VERSION 5.8 ;
BUSBITCHARS "[]" ;
DIVIDERCHAR "/" ;
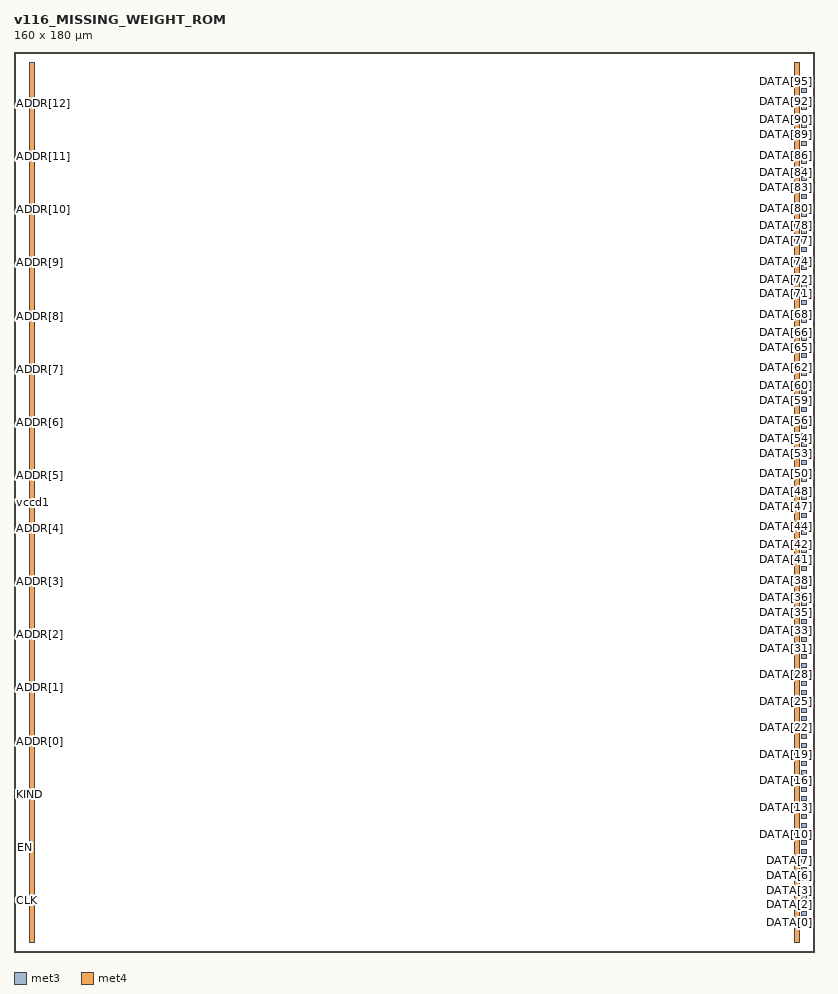
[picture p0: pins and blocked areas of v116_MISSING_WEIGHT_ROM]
MACRO v116_MISSING_WEIGHT_ROM
  CLASS BLOCK ;
  ORIGIN 0 0 ;
  FOREIGN v116_MISSING_WEIGHT_ROM 0 0 ;
  SIZE 160 BY 180 ;
  SYMMETRY X Y ;
  PIN CLK
   DIRECTION INPUT ;
   USE SIGNAL ;
   PORT
    LAYER met3 ;
    RECT 1.6000 9.9125 2.6000 10.7125 ;
   END
  END CLK
  PIN EN
   DIRECTION INPUT ;
   USE SIGNAL ;
   PORT
    LAYER met3 ;
    RECT 1.6000 20.5375 2.6000 21.3375 ;
   END
  END EN
  PIN KIND
   DIRECTION INPUT ;
   USE SIGNAL ;
   PORT
    LAYER met3 ;
    RECT 1.6000 31.1625 2.6000 31.9625 ;
   END
  END KIND
  PIN ADDR[0]
   DIRECTION INPUT ;
   USE SIGNAL ;
   PORT
    LAYER met3 ;
    RECT 1.6000 41.7875 2.6000 42.5875 ;
   END
  END ADDR[0]
  PIN ADDR[1]
   DIRECTION INPUT ;
   USE SIGNAL ;
   PORT
    LAYER met3 ;
    RECT 1.6000 52.4125 2.6000 53.2125 ;
   END
  END ADDR[1]
  PIN ADDR[2]
   DIRECTION INPUT ;
   USE SIGNAL ;
   PORT
    LAYER met3 ;
    RECT 1.6000 63.0375 2.6000 63.8375 ;
   END
  END ADDR[2]
  PIN ADDR[3]
   DIRECTION INPUT ;
   USE SIGNAL ;
   PORT
    LAYER met3 ;
    RECT 1.6000 73.6625 2.6000 74.4625 ;
   END
  END ADDR[3]
  PIN ADDR[4]
   DIRECTION INPUT ;
   USE SIGNAL ;
   PORT
    LAYER met3 ;
    RECT 1.6000 84.2875 2.6000 85.0875 ;
   END
  END ADDR[4]
  PIN ADDR[5]
   DIRECTION INPUT ;
   USE SIGNAL ;
   PORT
    LAYER met3 ;
    RECT 1.6000 94.9125 2.6000 95.7125 ;
   END
  END ADDR[5]
  PIN ADDR[6]
   DIRECTION INPUT ;
   USE SIGNAL ;
   PORT
    LAYER met3 ;
    RECT 1.6000 105.5375 2.6000 106.3375 ;
   END
  END ADDR[6]
  PIN ADDR[7]
   DIRECTION INPUT ;
   USE SIGNAL ;
   PORT
    LAYER met3 ;
    RECT 1.6000 116.1625 2.6000 116.9625 ;
   END
  END ADDR[7]
  PIN ADDR[8]
   DIRECTION INPUT ;
   USE SIGNAL ;
   PORT
    LAYER met3 ;
    RECT 1.6000 126.7875 2.6000 127.5875 ;
   END
  END ADDR[8]
  PIN ADDR[9]
   DIRECTION INPUT ;
   USE SIGNAL ;
   PORT
    LAYER met3 ;
    RECT 1.6000 137.4125 2.6000 138.2125 ;
   END
  END ADDR[9]
  PIN ADDR[10]
   DIRECTION INPUT ;
   USE SIGNAL ;
   PORT
    LAYER met3 ;
    RECT 1.6000 148.0375 2.6000 148.8375 ;
   END
  END ADDR[10]
  PIN ADDR[11]
   DIRECTION INPUT ;
   USE SIGNAL ;
   PORT
    LAYER met3 ;
    RECT 1.6000 158.6625 2.6000 159.4625 ;
   END
  END ADDR[11]
  PIN ADDR[12]
   DIRECTION INPUT ;
   USE SIGNAL ;
   PORT
    LAYER met3 ;
    RECT 1.6000 169.2875 2.6000 170.0875 ;
   END
  END ADDR[12]
  PIN DATA[0]
   DIRECTION OUTPUT ;
   USE SIGNAL ;
   PORT
    LAYER met3 ;
    RECT 157.4000 5.4854 158.4000 6.2854 ;
   END
  END DATA[0]
  PIN DATA[1]
   DIRECTION OUTPUT ;
   USE SIGNAL ;
   PORT
    LAYER met3 ;
    RECT 157.4000 7.2562 158.4000 8.0563 ;
   END
  END DATA[1]
  PIN DATA[2]
   DIRECTION OUTPUT ;
   USE SIGNAL ;
   PORT
    LAYER met3 ;
    RECT 157.4000 9.0271 158.4000 9.8271 ;
   END
  END DATA[2]
  PIN DATA[3]
   DIRECTION OUTPUT ;
   USE SIGNAL ;
   PORT
    LAYER met3 ;
    RECT 157.4000 10.7979 158.4000 11.5979 ;
   END
  END DATA[3]
  PIN DATA[4]
   DIRECTION OUTPUT ;
   USE SIGNAL ;
   PORT
    LAYER met3 ;
    RECT 157.4000 12.5687 158.4000 13.3688 ;
   END
  END DATA[4]
  PIN DATA[5]
   DIRECTION OUTPUT ;
   USE SIGNAL ;
   PORT
    LAYER met3 ;
    RECT 157.4000 14.3396 158.4000 15.1396 ;
   END
  END DATA[5]
  PIN DATA[6]
   DIRECTION OUTPUT ;
   USE SIGNAL ;
   PORT
    LAYER met3 ;
    RECT 157.4000 16.1104 158.4000 16.9104 ;
   END
  END DATA[6]
  PIN DATA[7]
   DIRECTION OUTPUT ;
   USE SIGNAL ;
   PORT
    LAYER met3 ;
    RECT 157.4000 17.8813 158.4000 18.6812 ;
   END
  END DATA[7]
  PIN DATA[8]
   DIRECTION OUTPUT ;
   USE SIGNAL ;
   PORT
    LAYER met3 ;
    RECT 157.4000 19.6521 158.4000 20.4521 ;
   END
  END DATA[8]
  PIN DATA[9]
   DIRECTION OUTPUT ;
   USE SIGNAL ;
   PORT
    LAYER met3 ;
    RECT 157.4000 21.4229 158.4000 22.2229 ;
   END
  END DATA[9]
  PIN DATA[10]
   DIRECTION OUTPUT ;
   USE SIGNAL ;
   PORT
    LAYER met3 ;
    RECT 157.4000 23.1938 158.4000 23.9937 ;
   END
  END DATA[10]
  PIN DATA[11]
   DIRECTION OUTPUT ;
   USE SIGNAL ;
   PORT
    LAYER met3 ;
    RECT 157.4000 24.9646 158.4000 25.7646 ;
   END
  END DATA[11]
  PIN DATA[12]
   DIRECTION OUTPUT ;
   USE SIGNAL ;
   PORT
    LAYER met3 ;
    RECT 157.4000 26.7354 158.4000 27.5354 ;
   END
  END DATA[12]
  PIN DATA[13]
   DIRECTION OUTPUT ;
   USE SIGNAL ;
   PORT
    LAYER met3 ;
    RECT 157.4000 28.5063 158.4000 29.3062 ;
   END
  END DATA[13]
  PIN DATA[14]
   DIRECTION OUTPUT ;
   USE SIGNAL ;
   PORT
    LAYER met3 ;
    RECT 157.4000 30.2771 158.4000 31.0771 ;
   END
  END DATA[14]
  PIN DATA[15]
   DIRECTION OUTPUT ;
   USE SIGNAL ;
   PORT
    LAYER met3 ;
    RECT 157.4000 32.0479 158.4000 32.8479 ;
   END
  END DATA[15]
  PIN DATA[16]
   DIRECTION OUTPUT ;
   USE SIGNAL ;
   PORT
    LAYER met3 ;
    RECT 157.4000 33.8188 158.4000 34.6187 ;
   END
  END DATA[16]
  PIN DATA[17]
   DIRECTION OUTPUT ;
   USE SIGNAL ;
   PORT
    LAYER met3 ;
    RECT 157.4000 35.5896 158.4000 36.3896 ;
   END
  END DATA[17]
  PIN DATA[18]
   DIRECTION OUTPUT ;
   USE SIGNAL ;
   PORT
    LAYER met3 ;
    RECT 157.4000 37.3604 158.4000 38.1604 ;
   END
  END DATA[18]
  PIN DATA[19]
   DIRECTION OUTPUT ;
   USE SIGNAL ;
   PORT
    LAYER met3 ;
    RECT 157.4000 39.1313 158.4000 39.9312 ;
   END
  END DATA[19]
  PIN DATA[20]
   DIRECTION OUTPUT ;
   USE SIGNAL ;
   PORT
    LAYER met3 ;
    RECT 157.4000 40.9021 158.4000 41.7021 ;
   END
  END DATA[20]
  PIN DATA[21]
   DIRECTION OUTPUT ;
   USE SIGNAL ;
   PORT
    LAYER met3 ;
    RECT 157.4000 42.6729 158.4000 43.4729 ;
   END
  END DATA[21]
  PIN DATA[22]
   DIRECTION OUTPUT ;
   USE SIGNAL ;
   PORT
    LAYER met3 ;
    RECT 157.4000 44.4438 158.4000 45.2437 ;
   END
  END DATA[22]
  PIN DATA[23]
   DIRECTION OUTPUT ;
   USE SIGNAL ;
   PORT
    LAYER met3 ;
    RECT 157.4000 46.2146 158.4000 47.0146 ;
   END
  END DATA[23]
  PIN DATA[24]
   DIRECTION OUTPUT ;
   USE SIGNAL ;
   PORT
    LAYER met3 ;
    RECT 157.4000 47.9854 158.4000 48.7854 ;
   END
  END DATA[24]
  PIN DATA[25]
   DIRECTION OUTPUT ;
   USE SIGNAL ;
   PORT
    LAYER met3 ;
    RECT 157.4000 49.7563 158.4000 50.5562 ;
   END
  END DATA[25]
  PIN DATA[26]
   DIRECTION OUTPUT ;
   USE SIGNAL ;
   PORT
    LAYER met3 ;
    RECT 157.4000 51.5271 158.4000 52.3271 ;
   END
  END DATA[26]
  PIN DATA[27]
   DIRECTION OUTPUT ;
   USE SIGNAL ;
   PORT
    LAYER met3 ;
    RECT 157.4000 53.2979 158.4000 54.0979 ;
   END
  END DATA[27]
  PIN DATA[28]
   DIRECTION OUTPUT ;
   USE SIGNAL ;
   PORT
    LAYER met3 ;
    RECT 157.4000 55.0688 158.4000 55.8687 ;
   END
  END DATA[28]
  PIN DATA[29]
   DIRECTION OUTPUT ;
   USE SIGNAL ;
   PORT
    LAYER met3 ;
    RECT 157.4000 56.8396 158.4000 57.6396 ;
   END
  END DATA[29]
  PIN DATA[30]
   DIRECTION OUTPUT ;
   USE SIGNAL ;
   PORT
    LAYER met3 ;
    RECT 157.4000 58.6104 158.4000 59.4104 ;
   END
  END DATA[30]
  PIN DATA[31]
   DIRECTION OUTPUT ;
   USE SIGNAL ;
   PORT
    LAYER met3 ;
    RECT 157.4000 60.3813 158.4000 61.1812 ;
   END
  END DATA[31]
  PIN DATA[32]
   DIRECTION OUTPUT ;
   USE SIGNAL ;
   PORT
    LAYER met3 ;
    RECT 157.4000 62.1521 158.4000 62.9521 ;
   END
  END DATA[32]
  PIN DATA[33]
   DIRECTION OUTPUT ;
   USE SIGNAL ;
   PORT
    LAYER met3 ;
    RECT 157.4000 63.9229 158.4000 64.7229 ;
   END
  END DATA[33]
  PIN DATA[34]
   DIRECTION OUTPUT ;
   USE SIGNAL ;
   PORT
    LAYER met3 ;
    RECT 157.4000 65.6937 158.4000 66.4938 ;
   END
  END DATA[34]
  PIN DATA[35]
   DIRECTION OUTPUT ;
   USE SIGNAL ;
   PORT
    LAYER met3 ;
    RECT 157.4000 67.4646 158.4000 68.2646 ;
   END
  END DATA[35]
  PIN DATA[36]
   DIRECTION OUTPUT ;
   USE SIGNAL ;
   PORT
    LAYER met3 ;
    RECT 157.4000 69.2354 158.4000 70.0354 ;
   END
  END DATA[36]
  PIN DATA[37]
   DIRECTION OUTPUT ;
   USE SIGNAL ;
   PORT
    LAYER met3 ;
    RECT 157.4000 71.0062 158.4000 71.8063 ;
   END
  END DATA[37]
  PIN DATA[38]
   DIRECTION OUTPUT ;
   USE SIGNAL ;
   PORT
    LAYER met3 ;
    RECT 157.4000 72.7771 158.4000 73.5771 ;
   END
  END DATA[38]
  PIN DATA[39]
   DIRECTION OUTPUT ;
   USE SIGNAL ;
   PORT
    LAYER met3 ;
    RECT 157.4000 74.5479 158.4000 75.3479 ;
   END
  END DATA[39]
  PIN DATA[40]
   DIRECTION OUTPUT ;
   USE SIGNAL ;
   PORT
    LAYER met3 ;
    RECT 157.4000 76.3187 158.4000 77.1188 ;
   END
  END DATA[40]
  PIN DATA[41]
   DIRECTION OUTPUT ;
   USE SIGNAL ;
   PORT
    LAYER met3 ;
    RECT 157.4000 78.0896 158.4000 78.8896 ;
   END
  END DATA[41]
  PIN DATA[42]
   DIRECTION OUTPUT ;
   USE SIGNAL ;
   PORT
    LAYER met3 ;
    RECT 157.4000 79.8604 158.4000 80.6604 ;
   END
  END DATA[42]
  PIN DATA[43]
   DIRECTION OUTPUT ;
   USE SIGNAL ;
   PORT
    LAYER met3 ;
    RECT 157.4000 81.6312 158.4000 82.4313 ;
   END
  END DATA[43]
  PIN DATA[44]
   DIRECTION OUTPUT ;
   USE SIGNAL ;
   PORT
    LAYER met3 ;
    RECT 157.4000 83.4021 158.4000 84.2021 ;
   END
  END DATA[44]
  PIN DATA[45]
   DIRECTION OUTPUT ;
   USE SIGNAL ;
   PORT
    LAYER met3 ;
    RECT 157.4000 85.1729 158.4000 85.9729 ;
   END
  END DATA[45]
  PIN DATA[46]
   DIRECTION OUTPUT ;
   USE SIGNAL ;
   PORT
    LAYER met3 ;
    RECT 157.4000 86.9437 158.4000 87.7438 ;
   END
  END DATA[46]
  PIN DATA[47]
   DIRECTION OUTPUT ;
   USE SIGNAL ;
   PORT
    LAYER met3 ;
    RECT 157.4000 88.7146 158.4000 89.5146 ;
   END
  END DATA[47]
  PIN DATA[48]
   DIRECTION OUTPUT ;
   USE SIGNAL ;
   PORT
    LAYER met3 ;
    RECT 157.4000 90.4854 158.4000 91.2854 ;
   END
  END DATA[48]
  PIN DATA[49]
   DIRECTION OUTPUT ;
   USE SIGNAL ;
   PORT
    LAYER met3 ;
    RECT 157.4000 92.2562 158.4000 93.0563 ;
   END
  END DATA[49]
  PIN DATA[50]
   DIRECTION OUTPUT ;
   USE SIGNAL ;
   PORT
    LAYER met3 ;
    RECT 157.4000 94.0271 158.4000 94.8271 ;
   END
  END DATA[50]
  PIN DATA[51]
   DIRECTION OUTPUT ;
   USE SIGNAL ;
   PORT
    LAYER met3 ;
    RECT 157.4000 95.7979 158.4000 96.5979 ;
   END
  END DATA[51]
  PIN DATA[52]
   DIRECTION OUTPUT ;
   USE SIGNAL ;
   PORT
    LAYER met3 ;
    RECT 157.4000 97.5687 158.4000 98.3688 ;
   END
  END DATA[52]
  PIN DATA[53]
   DIRECTION OUTPUT ;
   USE SIGNAL ;
   PORT
    LAYER met3 ;
    RECT 157.4000 99.3396 158.4000 100.1396 ;
   END
  END DATA[53]
  PIN DATA[54]
   DIRECTION OUTPUT ;
   USE SIGNAL ;
   PORT
    LAYER met3 ;
    RECT 157.4000 101.1104 158.4000 101.9104 ;
   END
  END DATA[54]
  PIN DATA[55]
   DIRECTION OUTPUT ;
   USE SIGNAL ;
   PORT
    LAYER met3 ;
    RECT 157.4000 102.8812 158.4000 103.6813 ;
   END
  END DATA[55]
  PIN DATA[56]
   DIRECTION OUTPUT ;
   USE SIGNAL ;
   PORT
    LAYER met3 ;
    RECT 157.4000 104.6521 158.4000 105.4521 ;
   END
  END DATA[56]
  PIN DATA[57]
   DIRECTION OUTPUT ;
   USE SIGNAL ;
   PORT
    LAYER met3 ;
    RECT 157.4000 106.4229 158.4000 107.2229 ;
   END
  END DATA[57]
  PIN DATA[58]
   DIRECTION OUTPUT ;
   USE SIGNAL ;
   PORT
    LAYER met3 ;
    RECT 157.4000 108.1937 158.4000 108.9938 ;
   END
  END DATA[58]
  PIN DATA[59]
   DIRECTION OUTPUT ;
   USE SIGNAL ;
   PORT
    LAYER met3 ;
    RECT 157.4000 109.9646 158.4000 110.7646 ;
   END
  END DATA[59]
  PIN DATA[60]
   DIRECTION OUTPUT ;
   USE SIGNAL ;
   PORT
    LAYER met3 ;
    RECT 157.4000 111.7354 158.4000 112.5354 ;
   END
  END DATA[60]
  PIN DATA[61]
   DIRECTION OUTPUT ;
   USE SIGNAL ;
   PORT
    LAYER met3 ;
    RECT 157.4000 113.5062 158.4000 114.3063 ;
   END
  END DATA[61]
  PIN DATA[62]
   DIRECTION OUTPUT ;
   USE SIGNAL ;
   PORT
    LAYER met3 ;
    RECT 157.4000 115.2771 158.4000 116.0771 ;
   END
  END DATA[62]
  PIN DATA[63]
   DIRECTION OUTPUT ;
   USE SIGNAL ;
   PORT
    LAYER met3 ;
    RECT 157.4000 117.0479 158.4000 117.8479 ;
   END
  END DATA[63]
  PIN DATA[64]
   DIRECTION OUTPUT ;
   USE SIGNAL ;
   PORT
    LAYER met3 ;
    RECT 157.4000 118.8187 158.4000 119.6188 ;
   END
  END DATA[64]
  PIN DATA[65]
   DIRECTION OUTPUT ;
   USE SIGNAL ;
   PORT
    LAYER met3 ;
    RECT 157.4000 120.5896 158.4000 121.3896 ;
   END
  END DATA[65]
  PIN DATA[66]
   DIRECTION OUTPUT ;
   USE SIGNAL ;
   PORT
    LAYER met3 ;
    RECT 157.4000 122.3604 158.4000 123.1604 ;
   END
  END DATA[66]
  PIN DATA[67]
   DIRECTION OUTPUT ;
   USE SIGNAL ;
   PORT
    LAYER met3 ;
    RECT 157.4000 124.1312 158.4000 124.9313 ;
   END
  END DATA[67]
  PIN DATA[68]
   DIRECTION OUTPUT ;
   USE SIGNAL ;
   PORT
    LAYER met3 ;
    RECT 157.4000 125.9021 158.4000 126.7021 ;
   END
  END DATA[68]
  PIN DATA[69]
   DIRECTION OUTPUT ;
   USE SIGNAL ;
   PORT
    LAYER met3 ;
    RECT 157.4000 127.6729 158.4000 128.4729 ;
   END
  END DATA[69]
  PIN DATA[70]
   DIRECTION OUTPUT ;
   USE SIGNAL ;
   PORT
    LAYER met3 ;
    RECT 157.4000 129.4437 158.4000 130.2438 ;
   END
  END DATA[70]
  PIN DATA[71]
   DIRECTION OUTPUT ;
   USE SIGNAL ;
   PORT
    LAYER met3 ;
    RECT 157.4000 131.2146 158.4000 132.0146 ;
   END
  END DATA[71]
  PIN DATA[72]
   DIRECTION OUTPUT ;
   USE SIGNAL ;
   PORT
    LAYER met3 ;
    RECT 157.4000 132.9854 158.4000 133.7854 ;
   END
  END DATA[72]
  PIN DATA[73]
   DIRECTION OUTPUT ;
   USE SIGNAL ;
   PORT
    LAYER met3 ;
    RECT 157.4000 134.7562 158.4000 135.5563 ;
   END
  END DATA[73]
  PIN DATA[74]
   DIRECTION OUTPUT ;
   USE SIGNAL ;
   PORT
    LAYER met3 ;
    RECT 157.4000 136.5271 158.4000 137.3271 ;
   END
  END DATA[74]
  PIN DATA[75]
   DIRECTION OUTPUT ;
   USE SIGNAL ;
   PORT
    LAYER met3 ;
    RECT 157.4000 138.2979 158.4000 139.0979 ;
   END
  END DATA[75]
  PIN DATA[76]
   DIRECTION OUTPUT ;
   USE SIGNAL ;
   PORT
    LAYER met3 ;
    RECT 157.4000 140.0687 158.4000 140.8688 ;
   END
  END DATA[76]
  PIN DATA[77]
   DIRECTION OUTPUT ;
   USE SIGNAL ;
   PORT
    LAYER met3 ;
    RECT 157.4000 141.8396 158.4000 142.6396 ;
   END
  END DATA[77]
  PIN DATA[78]
   DIRECTION OUTPUT ;
   USE SIGNAL ;
   PORT
    LAYER met3 ;
    RECT 157.4000 143.6104 158.4000 144.4104 ;
   END
  END DATA[78]
  PIN DATA[79]
   DIRECTION OUTPUT ;
   USE SIGNAL ;
   PORT
    LAYER met3 ;
    RECT 157.4000 145.3812 158.4000 146.1813 ;
   END
  END DATA[79]
  PIN DATA[80]
   DIRECTION OUTPUT ;
   USE SIGNAL ;
   PORT
    LAYER met3 ;
    RECT 157.4000 147.1521 158.4000 147.9521 ;
   END
  END DATA[80]
  PIN DATA[81]
   DIRECTION OUTPUT ;
   USE SIGNAL ;
   PORT
    LAYER met3 ;
    RECT 157.4000 148.9229 158.4000 149.7229 ;
   END
  END DATA[81]
  PIN DATA[82]
   DIRECTION OUTPUT ;
   USE SIGNAL ;
   PORT
    LAYER met3 ;
    RECT 157.4000 150.6937 158.4000 151.4938 ;
   END
  END DATA[82]
  PIN DATA[83]
   DIRECTION OUTPUT ;
   USE SIGNAL ;
   PORT
    LAYER met3 ;
    RECT 157.4000 152.4646 158.4000 153.2646 ;
   END
  END DATA[83]
  PIN DATA[84]
   DIRECTION OUTPUT ;
   USE SIGNAL ;
   PORT
    LAYER met3 ;
    RECT 157.4000 154.2354 158.4000 155.0354 ;
   END
  END DATA[84]
  PIN DATA[85]
   DIRECTION OUTPUT ;
   USE SIGNAL ;
   PORT
    LAYER met3 ;
    RECT 157.4000 156.0062 158.4000 156.8063 ;
   END
  END DATA[85]
  PIN DATA[86]
   DIRECTION OUTPUT ;
   USE SIGNAL ;
   PORT
    LAYER met3 ;
    RECT 157.4000 157.7771 158.4000 158.5771 ;
   END
  END DATA[86]
  PIN DATA[87]
   DIRECTION OUTPUT ;
   USE SIGNAL ;
   PORT
    LAYER met3 ;
    RECT 157.4000 159.5479 158.4000 160.3479 ;
   END
  END DATA[87]
  PIN DATA[88]
   DIRECTION OUTPUT ;
   USE SIGNAL ;
   PORT
    LAYER met3 ;
    RECT 157.4000 161.3187 158.4000 162.1188 ;
   END
  END DATA[88]
  PIN DATA[89]
   DIRECTION OUTPUT ;
   USE SIGNAL ;
   PORT
    LAYER met3 ;
    RECT 157.4000 163.0896 158.4000 163.8896 ;
   END
  END DATA[89]
  PIN DATA[90]
   DIRECTION OUTPUT ;
   USE SIGNAL ;
   PORT
    LAYER met3 ;
    RECT 157.4000 164.8604 158.4000 165.6604 ;
   END
  END DATA[90]
  PIN DATA[91]
   DIRECTION OUTPUT ;
   USE SIGNAL ;
   PORT
    LAYER met3 ;
    RECT 157.4000 166.6312 158.4000 167.4313 ;
   END
  END DATA[91]
  PIN DATA[92]
   DIRECTION OUTPUT ;
   USE SIGNAL ;
   PORT
    LAYER met3 ;
    RECT 157.4000 168.4021 158.4000 169.2021 ;
   END
  END DATA[92]
  PIN DATA[93]
   DIRECTION OUTPUT ;
   USE SIGNAL ;
   PORT
    LAYER met3 ;
    RECT 157.4000 170.1729 158.4000 170.9729 ;
   END
  END DATA[93]
  PIN DATA[94]
   DIRECTION OUTPUT ;
   USE SIGNAL ;
   PORT
    LAYER met3 ;
    RECT 157.4000 171.9437 158.4000 172.7438 ;
   END
  END DATA[94]
  PIN DATA[95]
   DIRECTION OUTPUT ;
   USE SIGNAL ;
   PORT
    LAYER met3 ;
    RECT 157.4000 173.7146 158.4000 174.5146 ;
   END
  END DATA[95]
  PIN vccd1
   DIRECTION INOUT ;
   USE POWER ;
   PORT
    LAYER met4 ;
    RECT 3 2 4 178 ;
   END
  END vccd1
  PIN vssd1
   DIRECTION INOUT ;
   USE GROUND ;
   PORT
    LAYER met4 ;
    RECT 156 2 157 178 ;
   END
  END vssd1
END v116_MISSING_WEIGHT_ROM
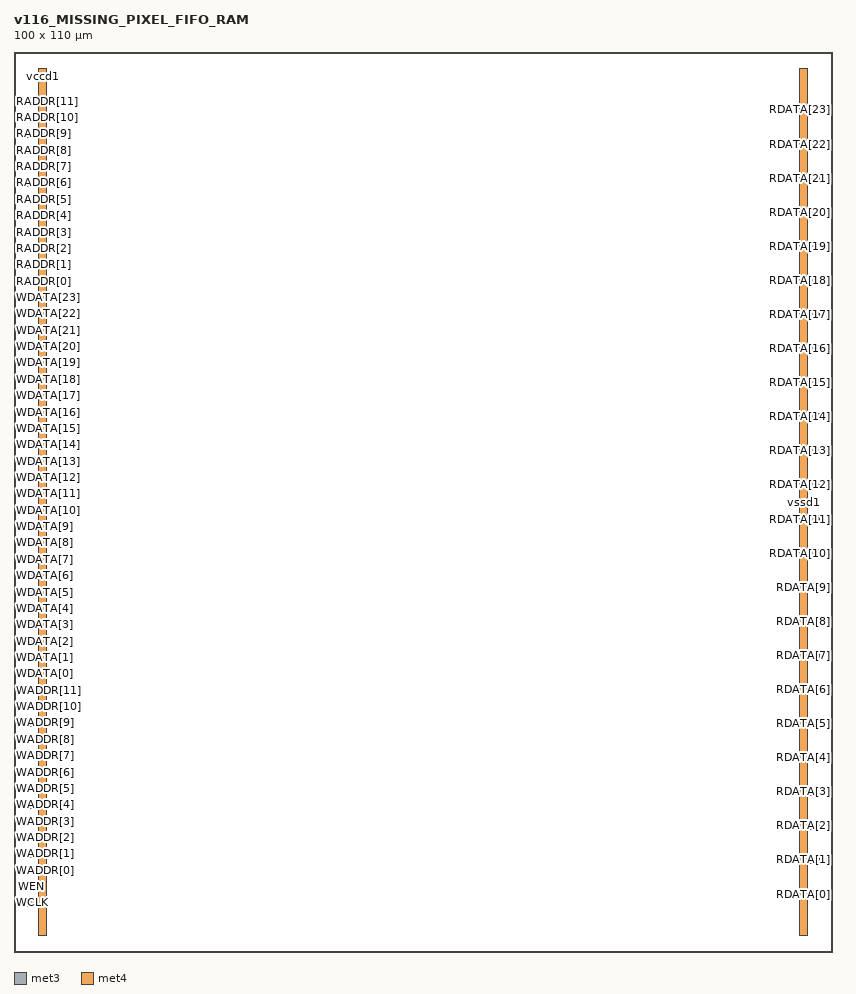
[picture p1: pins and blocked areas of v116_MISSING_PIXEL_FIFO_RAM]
MACRO v116_MISSING_PIXEL_FIFO_RAM
  CLASS BLOCK ;
  ORIGIN 0 0 ;
  FOREIGN v116_MISSING_PIXEL_FIFO_RAM 0 0 ;
  SIZE 100 BY 110 ;
  SYMMETRY X Y ;
  PIN WCLK
   DIRECTION INPUT ;
   USE SIGNAL ;
   PORT
    LAYER met3 ;
    RECT 1.6000 5.6000 2.6000 6.4000 ;
   END
  END WCLK
  PIN WEN
   DIRECTION INPUT ;
   USE SIGNAL ;
   PORT
    LAYER met3 ;
    RECT 1.6000 7.6000 2.6000 8.4000 ;
   END
  END WEN
  PIN WADDR[0]
   DIRECTION INPUT ;
   USE SIGNAL ;
   PORT
    LAYER met3 ;
    RECT 1.6000 9.6000 2.6000 10.4000 ;
   END
  END WADDR[0]
  PIN WADDR[1]
   DIRECTION INPUT ;
   USE SIGNAL ;
   PORT
    LAYER met3 ;
    RECT 1.6000 11.6000 2.6000 12.4000 ;
   END
  END WADDR[1]
  PIN WADDR[2]
   DIRECTION INPUT ;
   USE SIGNAL ;
   PORT
    LAYER met3 ;
    RECT 1.6000 13.6000 2.6000 14.4000 ;
   END
  END WADDR[2]
  PIN WADDR[3]
   DIRECTION INPUT ;
   USE SIGNAL ;
   PORT
    LAYER met3 ;
    RECT 1.6000 15.6000 2.6000 16.4000 ;
   END
  END WADDR[3]
  PIN WADDR[4]
   DIRECTION INPUT ;
   USE SIGNAL ;
   PORT
    LAYER met3 ;
    RECT 1.6000 17.6000 2.6000 18.4000 ;
   END
  END WADDR[4]
  PIN WADDR[5]
   DIRECTION INPUT ;
   USE SIGNAL ;
   PORT
    LAYER met3 ;
    RECT 1.6000 19.6000 2.6000 20.4000 ;
   END
  END WADDR[5]
  PIN WADDR[6]
   DIRECTION INPUT ;
   USE SIGNAL ;
   PORT
    LAYER met3 ;
    RECT 1.6000 21.6000 2.6000 22.4000 ;
   END
  END WADDR[6]
  PIN WADDR[7]
   DIRECTION INPUT ;
   USE SIGNAL ;
   PORT
    LAYER met3 ;
    RECT 1.6000 23.6000 2.6000 24.4000 ;
   END
  END WADDR[7]
  PIN WADDR[8]
   DIRECTION INPUT ;
   USE SIGNAL ;
   PORT
    LAYER met3 ;
    RECT 1.6000 25.6000 2.6000 26.4000 ;
   END
  END WADDR[8]
  PIN WADDR[9]
   DIRECTION INPUT ;
   USE SIGNAL ;
   PORT
    LAYER met3 ;
    RECT 1.6000 27.6000 2.6000 28.4000 ;
   END
  END WADDR[9]
  PIN WADDR[10]
   DIRECTION INPUT ;
   USE SIGNAL ;
   PORT
    LAYER met3 ;
    RECT 1.6000 29.6000 2.6000 30.4000 ;
   END
  END WADDR[10]
  PIN WADDR[11]
   DIRECTION INPUT ;
   USE SIGNAL ;
   PORT
    LAYER met3 ;
    RECT 1.6000 31.6000 2.6000 32.4000 ;
   END
  END WADDR[11]
  PIN WDATA[0]
   DIRECTION INPUT ;
   USE SIGNAL ;
   PORT
    LAYER met3 ;
    RECT 1.6000 33.6000 2.6000 34.4000 ;
   END
  END WDATA[0]
  PIN WDATA[1]
   DIRECTION INPUT ;
   USE SIGNAL ;
   PORT
    LAYER met3 ;
    RECT 1.6000 35.6000 2.6000 36.4000 ;
   END
  END WDATA[1]
  PIN WDATA[2]
   DIRECTION INPUT ;
   USE SIGNAL ;
   PORT
    LAYER met3 ;
    RECT 1.6000 37.6000 2.6000 38.4000 ;
   END
  END WDATA[2]
  PIN WDATA[3]
   DIRECTION INPUT ;
   USE SIGNAL ;
   PORT
    LAYER met3 ;
    RECT 1.6000 39.6000 2.6000 40.4000 ;
   END
  END WDATA[3]
  PIN WDATA[4]
   DIRECTION INPUT ;
   USE SIGNAL ;
   PORT
    LAYER met3 ;
    RECT 1.6000 41.6000 2.6000 42.4000 ;
   END
  END WDATA[4]
  PIN WDATA[5]
   DIRECTION INPUT ;
   USE SIGNAL ;
   PORT
    LAYER met3 ;
    RECT 1.6000 43.6000 2.6000 44.4000 ;
   END
  END WDATA[5]
  PIN WDATA[6]
   DIRECTION INPUT ;
   USE SIGNAL ;
   PORT
    LAYER met3 ;
    RECT 1.6000 45.6000 2.6000 46.4000 ;
   END
  END WDATA[6]
  PIN WDATA[7]
   DIRECTION INPUT ;
   USE SIGNAL ;
   PORT
    LAYER met3 ;
    RECT 1.6000 47.6000 2.6000 48.4000 ;
   END
  END WDATA[7]
  PIN WDATA[8]
   DIRECTION INPUT ;
   USE SIGNAL ;
   PORT
    LAYER met3 ;
    RECT 1.6000 49.6000 2.6000 50.4000 ;
   END
  END WDATA[8]
  PIN WDATA[9]
   DIRECTION INPUT ;
   USE SIGNAL ;
   PORT
    LAYER met3 ;
    RECT 1.6000 51.6000 2.6000 52.4000 ;
   END
  END WDATA[9]
  PIN WDATA[10]
   DIRECTION INPUT ;
   USE SIGNAL ;
   PORT
    LAYER met3 ;
    RECT 1.6000 53.6000 2.6000 54.4000 ;
   END
  END WDATA[10]
  PIN WDATA[11]
   DIRECTION INPUT ;
   USE SIGNAL ;
   PORT
    LAYER met3 ;
    RECT 1.6000 55.6000 2.6000 56.4000 ;
   END
  END WDATA[11]
  PIN WDATA[12]
   DIRECTION INPUT ;
   USE SIGNAL ;
   PORT
    LAYER met3 ;
    RECT 1.6000 57.6000 2.6000 58.4000 ;
   END
  END WDATA[12]
  PIN WDATA[13]
   DIRECTION INPUT ;
   USE SIGNAL ;
   PORT
    LAYER met3 ;
    RECT 1.6000 59.6000 2.6000 60.4000 ;
   END
  END WDATA[13]
  PIN WDATA[14]
   DIRECTION INPUT ;
   USE SIGNAL ;
   PORT
    LAYER met3 ;
    RECT 1.6000 61.6000 2.6000 62.4000 ;
   END
  END WDATA[14]
  PIN WDATA[15]
   DIRECTION INPUT ;
   USE SIGNAL ;
   PORT
    LAYER met3 ;
    RECT 1.6000 63.6000 2.6000 64.4000 ;
   END
  END WDATA[15]
  PIN WDATA[16]
   DIRECTION INPUT ;
   USE SIGNAL ;
   PORT
    LAYER met3 ;
    RECT 1.6000 65.6000 2.6000 66.4000 ;
   END
  END WDATA[16]
  PIN WDATA[17]
   DIRECTION INPUT ;
   USE SIGNAL ;
   PORT
    LAYER met3 ;
    RECT 1.6000 67.6000 2.6000 68.4000 ;
   END
  END WDATA[17]
  PIN WDATA[18]
   DIRECTION INPUT ;
   USE SIGNAL ;
   PORT
    LAYER met3 ;
    RECT 1.6000 69.6000 2.6000 70.4000 ;
   END
  END WDATA[18]
  PIN WDATA[19]
   DIRECTION INPUT ;
   USE SIGNAL ;
   PORT
    LAYER met3 ;
    RECT 1.6000 71.6000 2.6000 72.4000 ;
   END
  END WDATA[19]
  PIN WDATA[20]
   DIRECTION INPUT ;
   USE SIGNAL ;
   PORT
    LAYER met3 ;
    RECT 1.6000 73.6000 2.6000 74.4000 ;
   END
  END WDATA[20]
  PIN WDATA[21]
   DIRECTION INPUT ;
   USE SIGNAL ;
   PORT
    LAYER met3 ;
    RECT 1.6000 75.6000 2.6000 76.4000 ;
   END
  END WDATA[21]
  PIN WDATA[22]
   DIRECTION INPUT ;
   USE SIGNAL ;
   PORT
    LAYER met3 ;
    RECT 1.6000 77.6000 2.6000 78.4000 ;
   END
  END WDATA[22]
  PIN WDATA[23]
   DIRECTION INPUT ;
   USE SIGNAL ;
   PORT
    LAYER met3 ;
    RECT 1.6000 79.6000 2.6000 80.4000 ;
   END
  END WDATA[23]
  PIN RADDR[0]
   DIRECTION INPUT ;
   USE SIGNAL ;
   PORT
    LAYER met3 ;
    RECT 1.6000 81.6000 2.6000 82.4000 ;
   END
  END RADDR[0]
  PIN RADDR[1]
   DIRECTION INPUT ;
   USE SIGNAL ;
   PORT
    LAYER met3 ;
    RECT 1.6000 83.6000 2.6000 84.4000 ;
   END
  END RADDR[1]
  PIN RADDR[2]
   DIRECTION INPUT ;
   USE SIGNAL ;
   PORT
    LAYER met3 ;
    RECT 1.6000 85.6000 2.6000 86.4000 ;
   END
  END RADDR[2]
  PIN RADDR[3]
   DIRECTION INPUT ;
   USE SIGNAL ;
   PORT
    LAYER met3 ;
    RECT 1.6000 87.6000 2.6000 88.4000 ;
   END
  END RADDR[3]
  PIN RADDR[4]
   DIRECTION INPUT ;
   USE SIGNAL ;
   PORT
    LAYER met3 ;
    RECT 1.6000 89.6000 2.6000 90.4000 ;
   END
  END RADDR[4]
  PIN RADDR[5]
   DIRECTION INPUT ;
   USE SIGNAL ;
   PORT
    LAYER met3 ;
    RECT 1.6000 91.6000 2.6000 92.4000 ;
   END
  END RADDR[5]
  PIN RADDR[6]
   DIRECTION INPUT ;
   USE SIGNAL ;
   PORT
    LAYER met3 ;
    RECT 1.6000 93.6000 2.6000 94.4000 ;
   END
  END RADDR[6]
  PIN RADDR[7]
   DIRECTION INPUT ;
   USE SIGNAL ;
   PORT
    LAYER met3 ;
    RECT 1.6000 95.6000 2.6000 96.4000 ;
   END
  END RADDR[7]
  PIN RADDR[8]
   DIRECTION INPUT ;
   USE SIGNAL ;
   PORT
    LAYER met3 ;
    RECT 1.6000 97.6000 2.6000 98.4000 ;
   END
  END RADDR[8]
  PIN RADDR[9]
   DIRECTION INPUT ;
   USE SIGNAL ;
   PORT
    LAYER met3 ;
    RECT 1.6000 99.6000 2.6000 100.4000 ;
   END
  END RADDR[9]
  PIN RADDR[10]
   DIRECTION INPUT ;
   USE SIGNAL ;
   PORT
    LAYER met3 ;
    RECT 1.6000 101.6000 2.6000 102.4000 ;
   END
  END RADDR[10]
  PIN RADDR[11]
   DIRECTION INPUT ;
   USE SIGNAL ;
   PORT
    LAYER met3 ;
    RECT 1.6000 103.6000 2.6000 104.4000 ;
   END
  END RADDR[11]
  PIN RDATA[0]
   DIRECTION OUTPUT ;
   USE SIGNAL ;
   PORT
    LAYER met3 ;
    RECT 97.4000 6.6833 98.4000 7.4833 ;
   END
  END RDATA[0]
  PIN RDATA[1]
   DIRECTION OUTPUT ;
   USE SIGNAL ;
   PORT
    LAYER met3 ;
    RECT 97.4000 10.8500 98.4000 11.6500 ;
   END
  END RDATA[1]
  PIN RDATA[2]
   DIRECTION OUTPUT ;
   USE SIGNAL ;
   PORT
    LAYER met3 ;
    RECT 97.4000 15.0167 98.4000 15.8167 ;
   END
  END RDATA[2]
  PIN RDATA[3]
   DIRECTION OUTPUT ;
   USE SIGNAL ;
   PORT
    LAYER met3 ;
    RECT 97.4000 19.1833 98.4000 19.9833 ;
   END
  END RDATA[3]
  PIN RDATA[4]
   DIRECTION OUTPUT ;
   USE SIGNAL ;
   PORT
    LAYER met3 ;
    RECT 97.4000 23.3500 98.4000 24.1500 ;
   END
  END RDATA[4]
  PIN RDATA[5]
   DIRECTION OUTPUT ;
   USE SIGNAL ;
   PORT
    LAYER met3 ;
    RECT 97.4000 27.5167 98.4000 28.3167 ;
   END
  END RDATA[5]
  PIN RDATA[6]
   DIRECTION OUTPUT ;
   USE SIGNAL ;
   PORT
    LAYER met3 ;
    RECT 97.4000 31.6833 98.4000 32.4833 ;
   END
  END RDATA[6]
  PIN RDATA[7]
   DIRECTION OUTPUT ;
   USE SIGNAL ;
   PORT
    LAYER met3 ;
    RECT 97.4000 35.8500 98.4000 36.6500 ;
   END
  END RDATA[7]
  PIN RDATA[8]
   DIRECTION OUTPUT ;
   USE SIGNAL ;
   PORT
    LAYER met3 ;
    RECT 97.4000 40.0167 98.4000 40.8167 ;
   END
  END RDATA[8]
  PIN RDATA[9]
   DIRECTION OUTPUT ;
   USE SIGNAL ;
   PORT
    LAYER met3 ;
    RECT 97.4000 44.1833 98.4000 44.9833 ;
   END
  END RDATA[9]
  PIN RDATA[10]
   DIRECTION OUTPUT ;
   USE SIGNAL ;
   PORT
    LAYER met3 ;
    RECT 97.4000 48.3500 98.4000 49.1500 ;
   END
  END RDATA[10]
  PIN RDATA[11]
   DIRECTION OUTPUT ;
   USE SIGNAL ;
   PORT
    LAYER met3 ;
    RECT 97.4000 52.5167 98.4000 53.3167 ;
   END
  END RDATA[11]
  PIN RDATA[12]
   DIRECTION OUTPUT ;
   USE SIGNAL ;
   PORT
    LAYER met3 ;
    RECT 97.4000 56.6833 98.4000 57.4833 ;
   END
  END RDATA[12]
  PIN RDATA[13]
   DIRECTION OUTPUT ;
   USE SIGNAL ;
   PORT
    LAYER met3 ;
    RECT 97.4000 60.8500 98.4000 61.6500 ;
   END
  END RDATA[13]
  PIN RDATA[14]
   DIRECTION OUTPUT ;
   USE SIGNAL ;
   PORT
    LAYER met3 ;
    RECT 97.4000 65.0167 98.4000 65.8167 ;
   END
  END RDATA[14]
  PIN RDATA[15]
   DIRECTION OUTPUT ;
   USE SIGNAL ;
   PORT
    LAYER met3 ;
    RECT 97.4000 69.1833 98.4000 69.9833 ;
   END
  END RDATA[15]
  PIN RDATA[16]
   DIRECTION OUTPUT ;
   USE SIGNAL ;
   PORT
    LAYER met3 ;
    RECT 97.4000 73.3500 98.4000 74.1500 ;
   END
  END RDATA[16]
  PIN RDATA[17]
   DIRECTION OUTPUT ;
   USE SIGNAL ;
   PORT
    LAYER met3 ;
    RECT 97.4000 77.5167 98.4000 78.3167 ;
   END
  END RDATA[17]
  PIN RDATA[18]
   DIRECTION OUTPUT ;
   USE SIGNAL ;
   PORT
    LAYER met3 ;
    RECT 97.4000 81.6833 98.4000 82.4833 ;
   END
  END RDATA[18]
  PIN RDATA[19]
   DIRECTION OUTPUT ;
   USE SIGNAL ;
   PORT
    LAYER met3 ;
    RECT 97.4000 85.8500 98.4000 86.6500 ;
   END
  END RDATA[19]
  PIN RDATA[20]
   DIRECTION OUTPUT ;
   USE SIGNAL ;
   PORT
    LAYER met3 ;
    RECT 97.4000 90.0167 98.4000 90.8167 ;
   END
  END RDATA[20]
  PIN RDATA[21]
   DIRECTION OUTPUT ;
   USE SIGNAL ;
   PORT
    LAYER met3 ;
    RECT 97.4000 94.1833 98.4000 94.9833 ;
   END
  END RDATA[21]
  PIN RDATA[22]
   DIRECTION OUTPUT ;
   USE SIGNAL ;
   PORT
    LAYER met3 ;
    RECT 97.4000 98.3500 98.4000 99.1500 ;
   END
  END RDATA[22]
  PIN RDATA[23]
   DIRECTION OUTPUT ;
   USE SIGNAL ;
   PORT
    LAYER met3 ;
    RECT 97.4000 102.5167 98.4000 103.3167 ;
   END
  END RDATA[23]
  PIN vccd1
   DIRECTION INOUT ;
   USE POWER ;
   PORT
    LAYER met4 ;
    RECT 3 2 4 108 ;
   END
  END vccd1
  PIN vssd1
   DIRECTION INOUT ;
   USE GROUND ;
   PORT
    LAYER met4 ;
    RECT 96 2 97 108 ;
   END
  END vssd1
END v116_MISSING_PIXEL_FIFO_RAM
END LIBRARY
